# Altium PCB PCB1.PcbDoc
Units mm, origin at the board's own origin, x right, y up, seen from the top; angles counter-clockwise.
Board outline 42.03 x 51.56 mm, 2 copper layers (Top Layer, Bottom Layer); 20 components, 15 nets, 72 pads, 21 vias.
Unrouted connection lines stored in the file: 12.

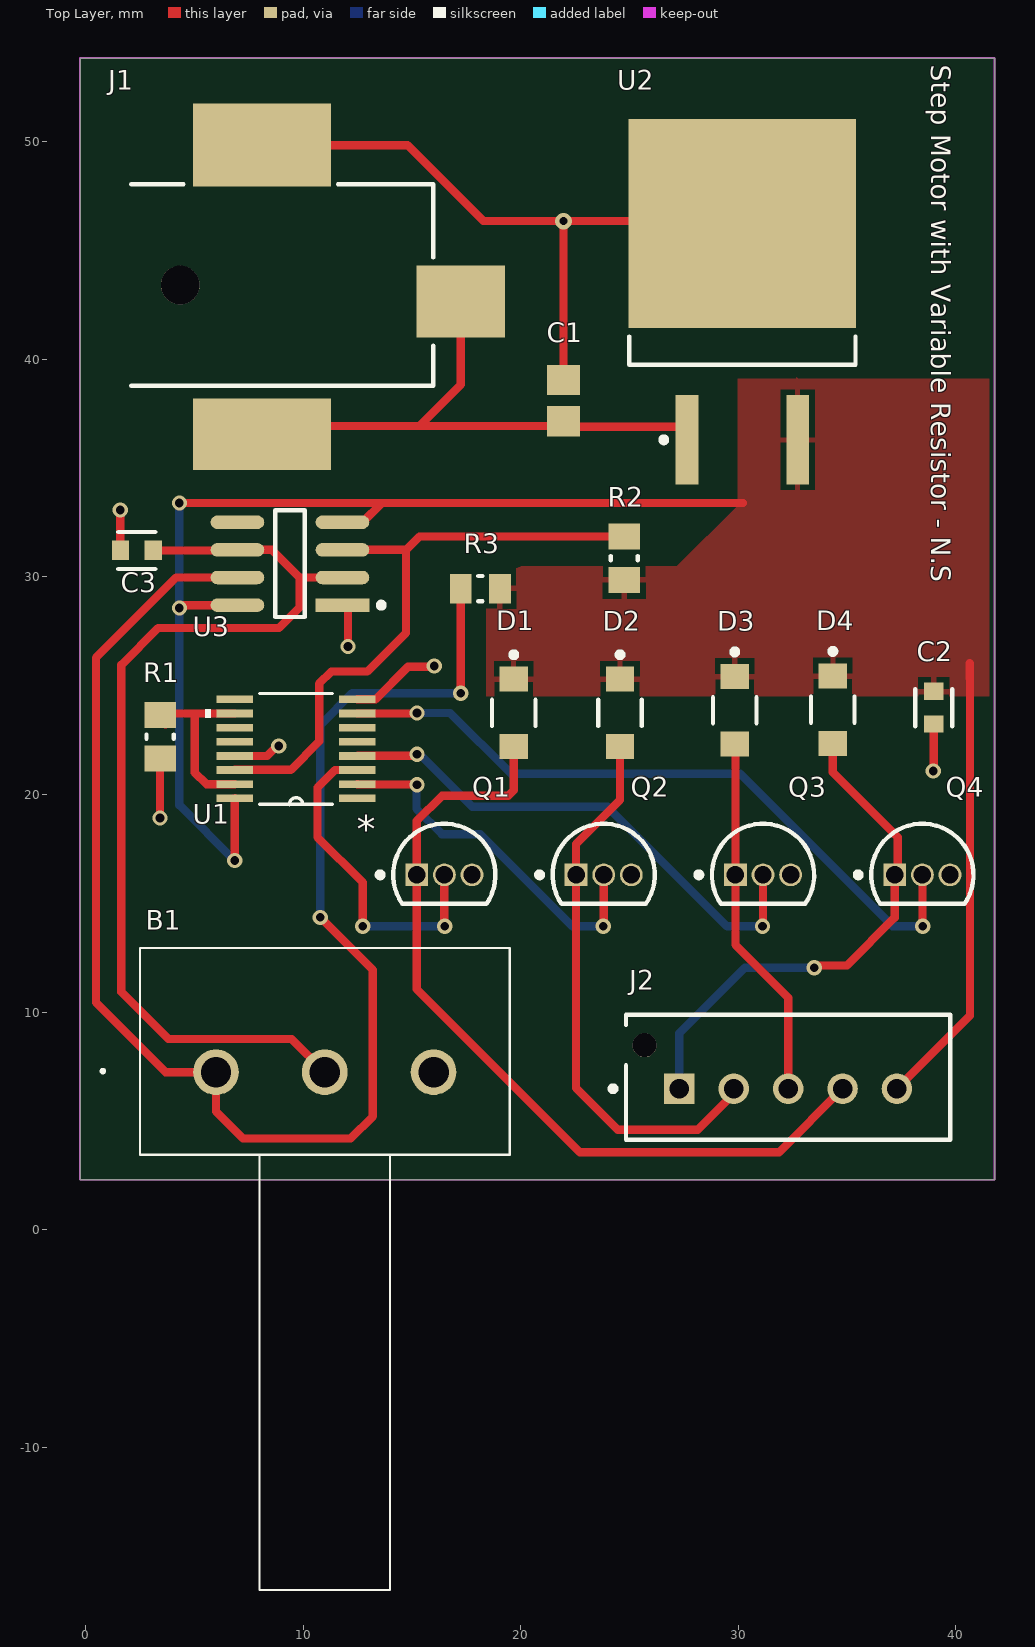
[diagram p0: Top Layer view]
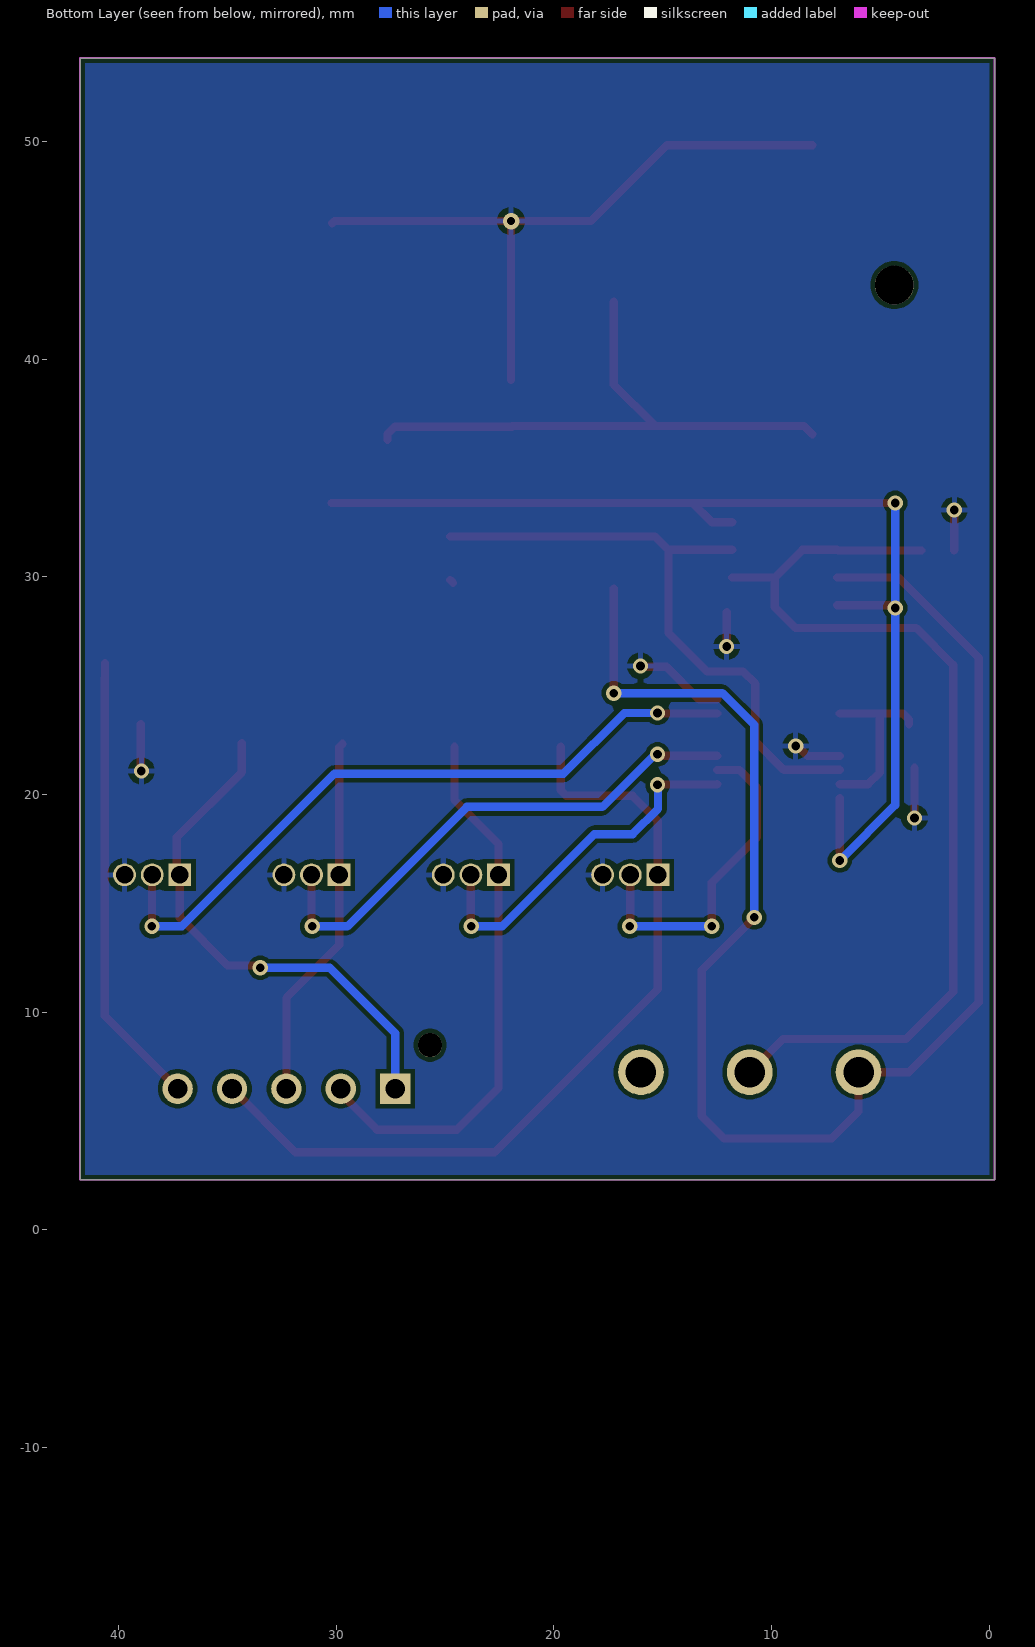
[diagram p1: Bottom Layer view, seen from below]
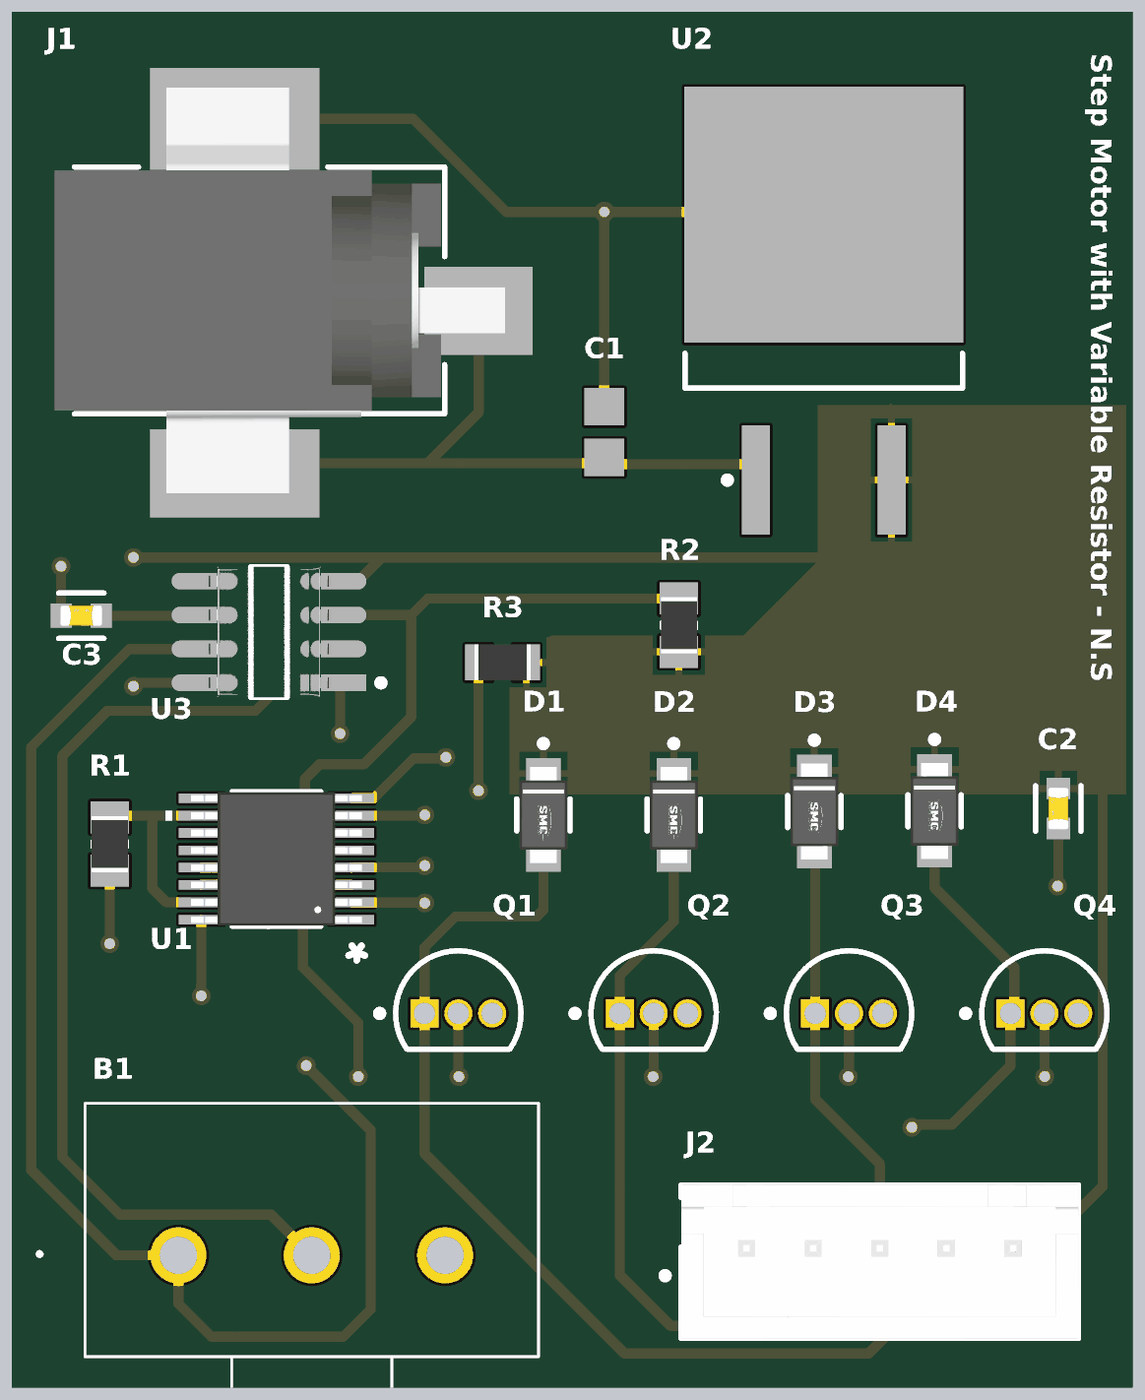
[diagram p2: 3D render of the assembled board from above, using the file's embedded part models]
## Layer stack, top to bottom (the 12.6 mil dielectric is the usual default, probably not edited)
Top Solder: solder mask 0.0102, Solder Resist, Dk 3.5
Top Layer: signal copper 0.6
Dielectric 1: dielectric 0.32, FR-4, Dk 4.8
Bottom Layer: signal copper 0.6
Bottom Solder: solder mask 0.0102, Solder Resist, Dk 3.5

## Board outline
-0.248,2.286 -0.248,53.848 41.783,53.848 41.783,2.286

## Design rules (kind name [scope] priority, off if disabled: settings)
Clearance [All] p1: gap=0.2 ignorepadtopadclearanceinfootprint=FALSE
MinimumSolderMaskSliver [All] p1: minsoldermaskwidth=0.001
PolygonConnect [All] p1: connectstyle=Relief reliefconductorwidth=0.254 reliefentries=4 polygonreliefangle="90 Angle" airgapwidth=0.254
RoutingVias [All] p1: holewidth=0.711 width=1.27 viastyle="Through Hole" minholewidth=0.3 minwidth=0.6 maxholewidth=0.711 maxwidth=1.27
SilkToSolderMaskClearance [IsPad] p1: minsilkscreentomaskgap=0.1 clearancetoexposedcopper=TRUE
SolderMaskExpansion [All] p1: expansion=0.102 istentingtop=FALSE
SupplyNets "Schematic Supply Nets_2" [InNet('GND')] p1: voltage=0.000
SupplyNets "Schematic Supply Nets_1" [InNet('+5')] p2: voltage=0.000
SupplyNets "Schematic Supply Nets" [InNet('+9')] p3: voltage=0.000
Width [All] p1: maxlimit=0.508 minlimit=0.254 preferedwidth=0.254
28 further rules are at their usual default settings.

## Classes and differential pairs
polygon class GND: +5_L01_P000

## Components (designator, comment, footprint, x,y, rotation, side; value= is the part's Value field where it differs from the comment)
B1 "P160KN-0QC20A10K" P160KN0QC20A10K 6.002,7.239 r0 top
C1 "0.33uF" CAPC2013X95X45ML10T25 21.971,38.1 r270 top
C2 "CC0603KRX7R7BB104" FP-CC0603-DA-MFG 38.989,23.991 r270 top value="100 nF"
C3 "0.1UF" FP-CC0603-DA-MFG 2.362,31.217 r180 top value="100 nF"
D1 "1N4007FL" FP-1N4007FL-MFG 19.685,23.749 r270 top
D2 "1N4007FL" FP-1N4007FL-MFG 24.573,23.749 r270 top
D3 "1N4007FL" FP-1N4007FL-MFG 29.843,23.876 r270 top
D4 "1N4007FL" FP-1N4007FL-MFG 34.35,23.902 r270 top
J1 "RASM722PTR13X" FP-RASM722PTR13X-MFG 8.606,43.413 r270 top
J2 "B5B-XH-AM(LF)(SN)" FP-B5B-XH-AM_LF_SN-MFG 32.298,7.002 r180 top
Q1 "BC337G" ONSC-TO-92-3-29-11 16.496,16.308 r0 top
Q2 "BC337G" ONSC-TO-92-3-29-11 23.819,16.308 r0 top
Q3 "BC337G" ONSC-TO-92-3-29-11 31.143,16.308 r0 top
Q4 "BC337G" ONSC-TO-92-3-29-11 38.467,16.308 r0 top
R1 "1 KOhm" RESC2013X60X35ML10T20 3.429,22.657 r270 top
R2 "1 KOhm" RESC2013X60X35ML10T20 24.765,30.861 r90 top
R3 "10 KOhm" RESC2013X60X35NL10T20 18.153,29.464 r0 top
U1 "CD4017BPWR" PW16 9.681,22.098 r180 top
U2 "L7805CD2T-TR" TO-263_M 30.196,42.651 r90 top
U3 "NE555DR" FP-D0008A-IPC_A 9.398,30.607 r180 top

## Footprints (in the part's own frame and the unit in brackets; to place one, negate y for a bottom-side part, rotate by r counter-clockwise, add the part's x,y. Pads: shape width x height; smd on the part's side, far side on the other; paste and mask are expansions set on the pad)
CAPC2013X95X45ML10T25 [mm] "Chip Capacitor, 2-Leads, Body 2.00x1.25mm, IPC Low Density"
  rect 1.4x1.5 smd: 1(-0.95,0) 2(0.95,0)
  body extent -1.05,-0.67 1.05,0.67, height 0.95
FP-1N4007FL-MFG [mm]
  rect 1.15x1.3 smd paste+0 mask+0: 1(-1.55,0) 2(1.55,0)
  silkscreen extent -2.8,-1 0.6,1, body extent -2.22,-1.1 2.22,1.1, height 0.25
FP-B5B-XH-AM_LF_SN-MFG [mm]
  rect 1.4x1.4 hole 0.9 paste-2539.97 mask+0: 1(5,0.525)
  round 1.4 hole 0.9 paste-2539.97 mask+0: 2(2.5,0.525) 3(0,0.525) 4(-2.5,0.525) 5(-5,0.525)
  round 1.1 hole 1.1 unplated paste-2539.97 mask+0: ""(6.6,-1.475)
  silkscreen extent -7.45,-2.88 8.17,2.88, body extent -7.45,-2.88 7.45,2.88, height 7
FP-CC0603-DA-MFG [mm]
  rect 0.8x0.9 smd paste+0 mask+0: 1(-0.75,0) 2(0.75,0)
  silkscreen extent -0.85,-0.85 0.85,0.85, body extent -1.35,-0.75 1.35,0.75, height 0.25
FP-D0008A-IPC_A [mm]
  rect 2.469x0.622 smd paste+0 mask+0: 1(-2.414,1.905)
  rrect100% 2.469x0.622 smd paste+0 mask+0: 2(-2.414,0.635) 3(-2.414,-0.635) 4(-2.414,-1.905) 5(2.414,-1.905) 6(2.414,-0.635) 7(2.414,0.635) 8(2.414,1.905)
  silkscreen extent -4.32,-2.45 0.68,2.45, body extent -4.15,-2.95 4.15,2.95, height 0.25
FP-RASM722PTR13X-MFG [mm]
  rect 3.3x4.06 smd paste+0 mask+0: 1(0.76,8.65)
  rect 3.81x6.35 smd paste+0 mask+0: 2(-6.43,-0.49)
  rect 3.3x6.35 smd paste+0 mask+0: 3(6.86,-0.49)
  round 1.78 hole 1.78 unplated paste-2539.97 mask+0: ""(0,-4.25)
  silkscreen extent -4.63,-6.5 4.63,7.38, body extent -8.43,-7.48 8.61,10.78, height 0.25
ONSC-TO-92-3-29-11 [mm] "TO, 3-Leads, Body Dia 4.7mm, Pitch 1.27mm"
  rect 1.05x1.05 hole 0.8: 1(-1.27,0)
  round 1.05 hole 0.8: 2(0,0) 3(1.27,0)
  silkscreen extent -3.07,-1.34 2.35,2.35, body extent -2.35,-1.33 2.36,2.36, height 7.87
P160KN0QC20A10K [mm]
  round 2.1 hole 1.4: 1(0,0) 2(5,0) 3(10,0)
  silkscreen extent -5.25,-23.8 13.5,5.7
PW16 [mil]
  rect 66x14 smd: 1(-111,89.57) 2(-111,63.98) 3(-111,38.39) 4(-111,12.8) 5(-111,-12.8) 6(-111,-38.39) 7(-111,-63.98) 8(-111,-89.57) 9(111,-89.57) 10(111,-63.98) 11(111,-38.39) 12(111,-12.8) 13(111,12.8) 14(111,38.39) 15(111,63.98) 16(111,89.57)
  silkscreen extent -66,-100 164,101, body extent -126,-98 126,98, height 47
RESC2013X60X35ML10T20 [mm] "Chip Resistor, 2-Leads, Body 2.1x1.35mm, IPC Low Density"
  rect 1.2x1.45 smd: 1(-1,0) 2(1,0)
  silkscreen extent -0.1,-0.63 0.1,0.63, body extent -1.05,-0.68 1.05,0.67, height 0.6
RESC2013X60X35NL10T20 [mm] "Chip Resistor, 2-Leads, Body 2.1x1.35mm, IPC Medium Density"
  rect 1x1.35 smd: 1(-0.9,0) 2(0.9,0)
  silkscreen extent -0.1,-0.58 0.1,0.58, body extent -1.05,-0.68 1.05,0.67, height 0.6
TO-263_M [mm] "D2-PAK, 4-Leads, Body 9.2x10.2mm, Pitch 2.54mm, Lead Span 15.4mm, IPC Low Density"
  rect 4.1x1.05 smd: 1(-6.35,2.54) 3(-6.35,-2.54)
  rect 9.6x10.45 smd: 4(3.6,0)
  silkscreen extent -6.47,-5.2 -1.6,5.2, body extent -2.9,-5.2 6.45,5.2, height 4.6

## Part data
B1: "Potentiometers 16mm Rotary Panel Potentiometer", Manufacturer_Name="TT Electronics", Mouser Part Number=858-P160KN-0QC20A10K
C1: library part CMP-1036-04606-2, "0.33uFGRM219R71H334KA88D", Manufacturer=Murata, Part Number=GRM219R71H334KA88D
C2: library part CMP-2000-05002-2, "CAP CER 0.1UF 16V X7R 0603", Capacitance="100 nF", Manufacturer=YAGEO, Package=CC0603-DA, Temperature="-55°C to +125°C", Temperature Characteristic=X7R, Temperature Coefficient=15%, Temperature Range High=+125°C, Temperature Range Low=-55°C, Tolerance=0.1, Voltage="16 V"
C3: library part CMP-2000-05002-2, "CAP CER 0.1UF 16V X7R 0603", Capacitance="100 nF", Manufacturer=YAGEO, Manufacturer Part Number=CC0603KRX7R7BB104, Package=CC0603-DA, Temperature="-55°C to +125°C", Temperature Characteristic=X7R, Temperature Coefficient=15%, Temperature Range High=+125°C, Temperature Range Low=-55°C, Tolerance=0.1, Voltage="16 V"
D1 D2 D3 D4: library part CMP-10078-122641204-1, "1N4007FL Diode Gen Purp 1KV 1A SOD123FL", Capacitance=6pF, Forward Current=1A, Max Forward Surge Current (Ifsm)=30A, Max Junction Temperature (Tj)=150°C, Max Repetitive Reverse Voltage (Vrrm)=1kV, Min Operating Temperature=-55°C, Peak Reverse Current=5µA
J1: library part CMP-47995-000002-1, "CONN PWR JACK 2.1X5.5MM SOLDER", Case/Package=SMD/SMT, Color=Black, Current Rating=5A, Package Quantity=120
J2: library part CMP-17439-000304-1, "CONN HEADER VERT 5POS 2.5MM", Color=Green, Contact Resistance=20mR, Flammability Rating="UL94 V-0", Housing Color=White, Insulation Color=Natural, Max Current Rating=3A, Max Operating Temperature=85°C, Max Voltage Rating (AC)=250V, Min Operating Temperature=-25°C
Q1 Q2 Q3 Q4: library part CMP-1048-01442-1, "Amplifier Transistor, NPN Silicon, 3-Pin TO-92, Pb-Free, Bulk Box", Manufacturer="On Semiconductor"
R1 R2: library part CMP-2100-03671-1, "Chip Resistor, 1 KOhm, +/- 1%, 125 mW, -55 to 155 degC, 0805 (2012 Metric), RoHS, Tape and Reel", Case Code (Imperial)=0805, Case Code (Metric)=2012, Manufacturer=Yageo, Max Operating Temperature=155degC, Max Power Dissipation=125mW, Min Operating Temperature=-55degC, Package Description="2-Pin Surface Mounted Device, Body 2 x 1.25 mm", Package Quantity=1, Resistance=1KOhm, Temperature Coefficient=100ppm/degreesC, Tolerance=1%, Voltage Rating=150V
R3: library part CMP-1659-00013-4, "Chip Resistor, 10 KOhm, +/- 1%, 0.125 W, -55 to 155 degC, 0805 (2012 Metric), RoHS, Tape and Reel", Manufacturer=Yageo, Max Operating Temperature="155 degC", Min Operating Temperature="-55 degC", Package Quantity=5000, Voltage Rating="150 V"
U1: "CMOS Decade Counter with 10 Decoded Outputs", Package="TSSOP-16 Texas Instruments"
U2: library part CMP-0244-00213-1, "Positive Voltage Regulator, 3-Pin D2PAK, Tape and Reel"
U3: library part CMP-1685-00007-2, "IC OSC SGL TIMER 100KHZ 8-SOIC", Case/Package=SOIC, Frequency=100kHz, High Level Output Current=-200mA, Low Level Output Current=200mA, Max Operating Temperature=70°C, Max Supply Voltage=16V, Min Operating Temperature=0°C, Min Supply Voltage=4.5V, Operating Supply Current=10mA, Package Quantity=2500, Quiescent Current=15mA

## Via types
v1: diameter 0.7, hole 0.4, Top Layer to Bottom Layer, tented both sides, 20 vias
v2: diameter 0.762, hole 0.381, Top Layer to Bottom Layer, tented both sides, 1 vias

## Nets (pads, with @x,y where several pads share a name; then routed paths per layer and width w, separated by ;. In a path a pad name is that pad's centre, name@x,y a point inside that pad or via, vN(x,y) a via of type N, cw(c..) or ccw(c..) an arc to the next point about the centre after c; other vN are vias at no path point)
0: Q1.2 U1.3 | length 15.6
  Top Layer w0.381: U1.3 11.471,21.123 10.668,20.32 10.668,18.034 12.747,15.955 v1(12.747,13.939) ; Q1.2 16.496,14.011 16.518,13.989 v1(16.518,13.939)
  Bottom Layer w0.381: v1(12.747,13.939) v1(16.518,13.939)
1: Q2.2 U1.2 | length 17.1
  Top Layer w0.381: U1.2 12.513,20.46 15.227,20.46 v1(15.24,20.447) ; v1(23.8,13.939) 23.819,13.959 Q2.2
  Bottom Layer w0.381: v1(15.24,20.447) 15.216,20.049 15.216,19.343 16.381,18.178 18.144,18.178 22.383,13.939 v1(23.8,13.939)
2: Q3.2 U1.4 | length 24.3
  Top Layer w0.381: U1.4 12.513,21.786 15.182,21.786 v1(15.24,21.844) ; v1(31.115,13.939) 31.143,13.967 Q3.2
  Bottom Layer w0.381: v1(15.24,21.844) 15.367,21.844 17.78,19.431 24.003,19.431 29.495,13.939 v1(31.115,13.939)
3: Q4.2 U1.7 | length 32.4
  Top Layer w0.381: U1.7 15.18,23.723 15.181,23.725 15.212,23.725 v1@15.214,23.723 ; Q4.2 38.474,16.3 38.474,13.946 v1(38.481,13.939)
  Bottom Layer w0.381: v1(15.24,23.749) 16.764,23.749 19.558,20.955 30.089,20.955 37.097,13.946 38.474,13.946 v1(38.481,13.939)
+5: C2.1 D1.1 D2.1 D3.1 D4.1 J2.5 R2.1 R3.2 U1.16 U2.3 U3.4 U3.8 | length 72.3
  Top Layer w0.381: v1(4.318,28.575) 4.445,28.702 U3.8 ; v1(4.318,33.401) 13.624,33.401 ; v1(6.861,16.967) 6.858,16.97 6.858,17.399 6.861,17.402 U1.16 ; U3.4 12.735,32.512 13.624,33.401 ; R2.1@24.64,29.736 R2.1 ; 30.226,33.401 13.624,33.401 ; J2.5 40.652,9.831 40.652,25.329 40.64,25.341 40.64,26.027
  Bottom Layer w0.381: v1(4.318,33.401) v1(4.318,28.575) 4.318,19.51 v1(6.861,16.967)
+9: C1.2 J1.1 J1.3 U2.1 | length 26.6
  Top Layer w0.381: J1.3 8.498,36.935 15.345,36.935 ; J1.1 17.256,38.846 15.345,36.935 ; U2.1 27.656,36.562 27.322,36.897 21.941,36.897 21.903,36.935 15.345,36.935
GND: C1.1 C2.2 C3.2 J1.2 Q1.3 Q2.3 Q3.3 Q4.3 R1.2 U1.8 U1.13 U2.4 U3.1 | length 45.1
  Top Layer w0.381: v1(1.6,33.071) 1.606,33.065 1.606,31.223 C3.2 ; v1(3.429,18.923) R1.2@3.429,21.225 ; U1.13 8.352,21.773 8.804,22.225 v1(8.89,22.225) ; J1.2 14.8,49.843 18.288,46.355 v2(21.971,46.355) ; U3.1@12.064,28.391 v1(12.065,26.797) ; U1.8 13.331,24.373 14.829,25.871 15.99,25.871 v1(16.027,25.908) ; C1.1 v2(21.971,46.355) ; U2.4 30.092,46.355 v2(21.971,46.355) ; v1@38.989,21.107 C2.2
  other v1: 38.964,21.082
NetB1_1: B1.1 R3.1 U3.7 | length 71.5
  Top Layer w0.381: U3.7 4.169,29.972 0.483,26.286 0.483,10.439 3.683,7.239 B1.1 6.002,5.428 7.239,4.191 12.192,4.191 13.208,5.207 13.208,11.938 v1(10.795,14.351) ; v1(17.253,24.657) R3.1
  Bottom Layer w0.381: v1(10.795,14.351) 10.795,23.19 12.262,24.657 v1(17.253,24.657)
NetB1_2: B1.2 C3.1 U3.2 U3.6 | length 45.8
  Top Layer w0.381: C3.1 U3.6@6.959,31.217 ; U3.6 8.584,31.242 9.728,30.098 9.854,29.972 ; B1.2 9.478,8.763 3.81,8.763 1.651,10.922 1.651,25.959 3.347,27.654 8.898,27.654 9.854,28.61 9.854,29.972 ; U3.2 9.854,29.972
NetR1_1: R1.1 U1.10 U1.15 | length 8.3
  Top Layer w0.381: R1.1@3.683,23.225 3.683,23.443 3.963,23.723 5.021,23.723 ; U1.15 5.562,20.473 5.021,21.014 5.021,23.723 ; U1.10 5.021,23.723
PWM: R2.2 U1.14 U3.3 | length 29.1
  Top Layer w0.381: U1.14 6.874,21.136 9.44,21.136 10.744,22.44 10.744,25.095 11.303,25.654 12.959,25.654 14.732,27.427 14.732,31.242 ; U3.3 14.732,31.242 ; R2.2 15.351,31.861 14.732,31.242
step0: D1.2 J2.4 Q1.1 | length 38.7
  Top Layer w0.381: D1.2 19.685,20.193 19.431,19.939 16.386,19.939 15.226,18.779 Q1.1 15.226,11.063 22.733,3.556 31.877,3.556 J2.4
step1: D2.2 J2.2 Q2.1 | length 25.5
  Top Layer w0.381: D2.2 24.573,19.747 22.549,17.723 Q2.1 22.549,6.508 24.46,4.597 28.143,4.597 29.798,6.252 J2.2
step2: D3.2 J2.3 Q3.1 | length 16.9
  Top Layer w0.381: D3.2@29.716,22.326 29.873,22.169 Q3.1 29.873,13.089 32.298,10.664 J2.3
step3: D4.2 J2.1 Q4.1 | length 24
  Top Layer w0.381: v1(33.5,12.04) 33.601,12.141 35.001,12.141 37.197,14.337 Q4.1 37.338,16.449 37.338,18.034 34.35,21.022 D4.2
  Bottom Layer w0.381: J2.1 27.298,9.027 30.311,12.04 v1(33.5,12.04)
pads on no net: B1.3 J1. J2. U1.1 U1.5 U1.6 U1.9 U1.11 U1.12 U3.5

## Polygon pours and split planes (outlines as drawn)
+5 on Top Layer "+5_L01_P000" (solid, pour order 0): 32.639,39.243 32.766,39.116 41.529,39.116 41.529,25.146 41.529,24.511 40.64,24.511 18.415,24.511 18.415,30.48 27.178,30.48 29.972,33.274 29.972,39.116 32.639,39.116 32.766,39.243
GND on Bottom Layer "GND_L02_P002" (solid, remove dead copper, pour order 2): 0,2.286 0,53.848 41.783,53.848 41.783,2.286
GND on Bottom Layer "GND" (solid, remove dead copper, pour order 1): 0,2.286 0,53.848 41.783,53.848 41.783,2.286

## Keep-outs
Keep-Out Layer:
  the board outline again, w0.076

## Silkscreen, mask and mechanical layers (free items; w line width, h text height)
Top Overlay:
  text "Step Motor with Variable Resistor - N.S" at 38.577,53.545 h1.52 r270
